VERSION 5.7 ;
  NOWIREEXTENSIONATPIN ON ;
  DIVIDERCHAR "/" ;
  BUSBITCHARS "[]" ;
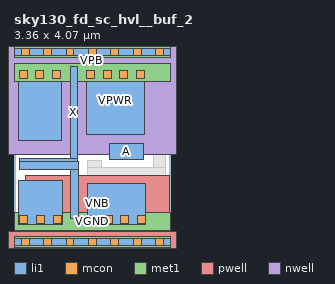
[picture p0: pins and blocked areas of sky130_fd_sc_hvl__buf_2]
MACRO sky130_fd_sc_hvl__buf_2
  CLASS BLOCK ;
  FOREIGN sky130_fd_sc_hvl__buf_2 ;
  ORIGIN 0.000 0.000 ;
  SIZE 3.360 BY 4.070 ;
  PIN A
    ANTENNAGATEAREA 0.585000 ;
    PORT
      LAYER li1 ;
        RECT 2.045 1.775 2.775 2.120 ;
    END
  END A
  PIN VGND
    USE GROUND ;
    PORT
      LAYER li1 ;
        RECT 0.090 0.365 1.040 1.325 ;
        RECT 1.570 0.365 2.820 1.245 ;
      LAYER mcon ;
        RECT 0.120 0.395 0.290 0.565 ;
        RECT 0.480 0.395 0.650 0.565 ;
        RECT 0.840 0.395 1.010 0.565 ;
        RECT 1.570 0.395 1.740 0.565 ;
        RECT 1.930 0.395 2.100 0.565 ;
        RECT 2.290 0.395 2.460 0.565 ;
        RECT 2.650 0.395 2.820 0.565 ;
      LAYER met1 ;
        RECT 0.000 0.255 3.360 0.625 ;
    END
  END VGND
  PIN VNB
    ANTENNADIFFAREA 0.571200 ;
    PORT
      LAYER pwell ;
        RECT 0.250 0.215 3.340 1.415 ;
        RECT -0.130 -0.215 3.490 0.215 ;
      LAYER li1 ;
        RECT 0.000 -0.085 3.360 0.085 ;
      LAYER mcon ;
        RECT 0.155 -0.085 0.325 0.085 ;
        RECT 0.635 -0.085 0.805 0.085 ;
        RECT 1.115 -0.085 1.285 0.085 ;
        RECT 1.595 -0.085 1.765 0.085 ;
        RECT 2.075 -0.085 2.245 0.085 ;
        RECT 2.555 -0.085 2.725 0.085 ;
        RECT 3.035 -0.085 3.205 0.085 ;
      LAYER met1 ;
        RECT 0.000 -0.115 3.360 0.115 ;
    END
  END VNB
  PIN VPB
    ANTENNADIFFAREA 0.571200 ;
    PORT
      LAYER nwell ;
        RECT -0.330 1.885 3.690 4.485 ;
      LAYER li1 ;
        RECT 0.000 3.985 3.360 4.155 ;
      LAYER mcon ;
        RECT 0.155 3.985 0.325 4.155 ;
        RECT 0.635 3.985 0.805 4.155 ;
        RECT 1.115 3.985 1.285 4.155 ;
        RECT 1.595 3.985 1.765 4.155 ;
        RECT 2.075 3.985 2.245 4.155 ;
        RECT 2.555 3.985 2.725 4.155 ;
        RECT 3.035 3.985 3.205 4.155 ;
      LAYER met1 ;
        RECT 0.000 3.955 3.360 4.185 ;
    END
  END VPB
  PIN VPWR
    USE POWER ;
    PORT
      LAYER li1 ;
        RECT 0.090 2.175 1.020 3.755 ;
        RECT 1.550 2.300 2.800 3.755 ;
      LAYER mcon ;
        RECT 0.110 3.505 0.280 3.675 ;
        RECT 0.470 3.505 0.640 3.675 ;
        RECT 0.830 3.505 1.000 3.675 ;
        RECT 1.550 3.505 1.720 3.675 ;
        RECT 1.910 3.505 2.080 3.675 ;
        RECT 2.270 3.505 2.440 3.675 ;
        RECT 2.630 3.505 2.800 3.675 ;
      LAYER met1 ;
        RECT 0.000 3.445 3.360 3.815 ;
    END
  END VPWR
  PIN X
    ANTENNADIFFAREA 0.630000 ;
    PORT
      LAYER li1 ;
        RECT 1.200 1.780 1.370 3.755 ;
        RECT 0.125 1.720 1.370 1.780 ;
        RECT 0.125 1.550 1.390 1.720 ;
        RECT 1.220 0.495 1.390 1.550 ;
    END
  END X
  OBS
      LAYER li1 ;
        RECT 1.570 1.595 1.865 1.755 ;
        RECT 2.980 1.595 3.250 3.005 ;
        RECT 1.570 1.425 3.250 1.595 ;
        RECT 3.000 0.825 3.250 1.425 ;
  END
END sky130_fd_sc_hvl__buf_2
END LIBRARY

